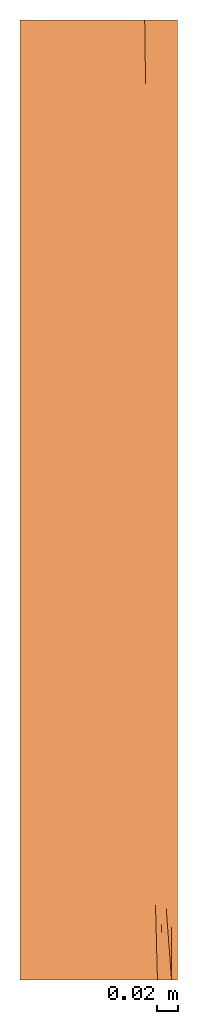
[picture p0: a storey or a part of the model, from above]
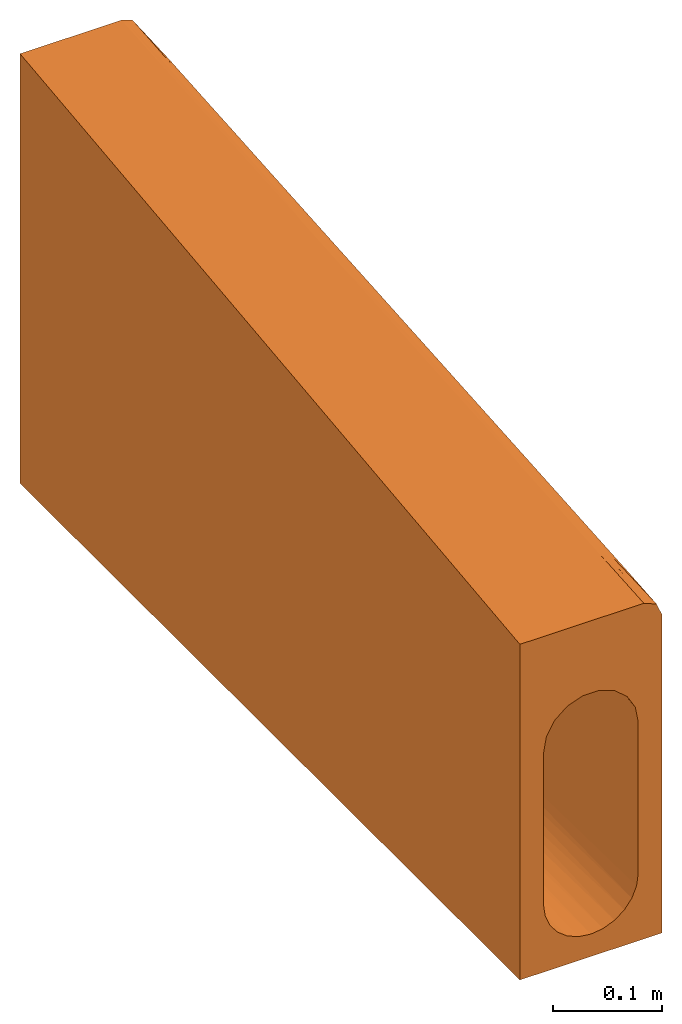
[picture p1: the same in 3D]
Properties of the parts of a building model (IFC2X3)

# File
Description: ViewDefinition [CoordinationView]
File name: 4932 - RH drop kerb - 915mm LG.ifc
Time: 2013-09-18T16:22:06
Written by: Autodesk Revit 2013
Made in: 20120221_2030(x64)

# IfcProject, Project Number
LongName: Project Name; Phase: Project Status

# IfcSite, Default
RefLatitude: 42, 21, 30, 344238; RefLongitude: -71, -3, -35, -194702; RefElevation: 0 mm

# IfcBuilding
Pset_BuildingCommon - NumberOfStoreys: 2
Other - Client Name: Owner; Project Name: Project Name; Project Number: Project Number; Project Status: Project Status; Project Address: Enter address here; Project Issue Date: Issue Date

# IfcBuildingStorey (2)
Constraints - Elevation Base: 0
Graphics - Line Pattern: Center; Symbol at End 2 Default: yes; Line Weight: 1; Symbol at End 1 Default: no; Color: 0; Symbol: M_Level Head - Circle: M_Level Head - Circle
Identity Data - Building Story: yes; Structural: no
Dimensions - Computation Height: 0 mm
Name | LongName = Name | Elevation (mm) = Constraints, Elevation (mm)
T.O. Fnd. Wall | T.O. Fnd. Wall | -300
Level 1 | Level 1 | 0

# IfcBuildingElementProxy: 4932 - RH drop kerb - 915mm LG, Civil-Drainage-Channel-ACO-KerbDrain-HB480(amar):4932 - RH drop kerb - 915mm LG:4932 - RH drop kerb - 915mm LG:481515
In: T.O. Fnd. Wall
Material: ACO Polymer Concrete.
Other - CreatedBy: www.aco.co.uk; Revision: 1
Materials and Finishes - Channel Colour: Grey; Access Cover/Frame Colour: N/A; Connection Pipe Material Colour: N/A; Channel Material: Vienite® Synthetic Resin Concrete; End Cap Colour: N/A; Access Cover/Frame Finish: N/A; Connection Pipe Material: N/A; Access Cover/Frame Material: N/A; End Cap Material: N/A
Phasing - Phase Created: Phase 1
Constraints - Moves With Nearby Elements: no; Level: Level: Level 1
Dimensions - Volume: 30548974 mm3; Void End I/O: 150 mm; Straight Void Start: 0 mm; Mitre Long end: 500 mm; I/O endcap void depth: 2000 mm; junction void depth: 2000 mm; Void Depth: -355 mm; Void Length: 915 mm; Mitre Void End: -5470 mm; Void Start I/O: 0 mm; Junction End: 150 mm; Void Width: 150 mm; Junction Start: 0 mm; Mitre Small End: 487 mm; Mitre Void Start: -5465 mm
Pset_BuildingElementProxyCommon - Reference: 4932 - RH drop kerb - 915mm LG
Green Building Properties - End Cap Recycled Material Content: N/A; End Cap Recyclable: N/A; Channel Recycled Material Content: 20% minimum; Channel Recyclable: Fully recyclable; Access Cover/Frame Recycled Material Content: N/A; Access Cover/Frame Recyclable: N/A
Identity Data - Product brochure: http://www.aco.co.uk/download.php?id=120; Product Code: 4932; Installation guidelines: http://www.aco.co.uk/download.php?id=120; Assembly Code: D2040; Cost: 0; OmniClass Number: 23.70.50.24; Type Comments: ACO KerbDrain HB480 half battered right-hand drop kerb unit 915mm long; Product Page URL: http://www.aco.co.uk/product_detail.php?id=3; OmniClass Title: Rainwater Removal; Telephone: +44 (0)1462 816666; URL: www.aco.co.uk; Maintenance guidelines: http://www.aco.co.uk/download.php?id=120; Model Description: Combined kerb and drainage system; Manufacturer: ACO Technologies plc - ACO Water Management Division; Price: POA - contact ACO; e-mail Technical: technical@aco.co.uk; e-mail Sales: customersupport@aco.co.uk; Address: ACO Business Park, Hitchin Road, Shefford, Bedfordshire, United Kingdom SG17 5TE; Model: ACO KerbDrain HB480; Fax: +44 (0)1462 815895; Assembly Description: Rain Water Drainage
Data - Drainage Slot Intake area: N/A; Installation - Concrete Grade: Refer to brochure; Channel C.S.A: 0.04 to 0.02mm²; Concrete Surround Volume - Load Class A 15 - D 400 - Concrete Pavement: N/A; Load Class: A 15 - D 400; ACO Hydraulic Design Software: http://www.acodesign.co.uk; Product Weight: 66.7 Kg; Drainage Slot Width: N/A; Hydraulic Performance: http://www.aco.co.uk/download.php?id=120; Invert Depth: 455/375mm; Connection Pipe O.D: N/A; Concrete Surround Volume - Load Class A 15 - D 400 - Grass or Asphalt Pavement: N/A; Product Dimensions: 915mm x 150mm x 480/375mm (LxWxH); Product Standard: BS EN 1433:2002, CE marked, Kitemarked
Construction - 10-8m external mitre: no; LH drop kerb: no; RH drop kerb: yes; 7-6m external mitre: no; Bus stop kerb: no; RH BS transition kerb: no; Centre Stone: no; Junction end cap: no; Junction channel: no; 25-11m internal mitre: no; LH BS transition kerb: no; Access Unit: no; LH inlet/outlet end cap: no; perforated centre stone: no; Junction access unit: no; 25-11m external mitre: no; cable loop: no; KDHB480 500_blindunit: no; Closing end cap: no; RH inlet/outlet end cap: no; HB480-500: no
General - TagNumber: 0.000000; SerialNumber: 0.000000

# IfcOpeningElement: Opening (3)
In: Level 1
Constraints - Level: Level: Level 1; Related to Mass: no; Height Offset From Level: 0 mm; Room Bounding: yes
Phasing - Phase Created: Phase 1
Structural - Structural: no; Enable Analytical Model: no
Dimensions - Volume: 2311976250 mm3; Thickness: 400 mm; Area: 5901750 mm2; Perimeter: 9790 mm
Graphics - Coarse Scale Fill Color: 0
Analytical Properties - Heat Transfer Coefficient (U): 2.0925; Thermal mass: 543920; Roughness: 1; Thermal Resistance (R): 0.477897; Absorptance: 0.1
Construction - Function: 0; Default Thickness: 400 mm
Materials and Finishes - Structural Material: Earth

# IfcSlab: Floor:Generic Floor - 400mm, Floor:Generic Floor - 400mm:136426
In: Level 1
PredefinedType: FLOOR; Material: Earth 400 mm
Constraints - Level: Level: Level 1; Related to Mass: no; Height Offset From Level: 0 mm; Room Bounding: yes
Phasing - Phase Created: Phase 1
Structural - Structural: no; Enable Analytical Model: no
Dimensions - Volume: 2311976250 mm3; Thickness: 400 mm; Area: 5901750 mm2; Perimeter: 9790 mm
Pset_SlabCommon - Reference: Generic Floor - 400mm; IsExternal: no; LoadBearing: yes
Graphics - Coarse Scale Fill Color: 0
Analytical Properties - Heat Transfer Coefficient (U): 2.0925; Thermal mass: 543920; Roughness: 1; Thermal Resistance (R): 0.477897; Absorptance: 0.1
Construction - Function: 0; Default Thickness: 400 mm
Materials and Finishes - Structural Material: Earth
